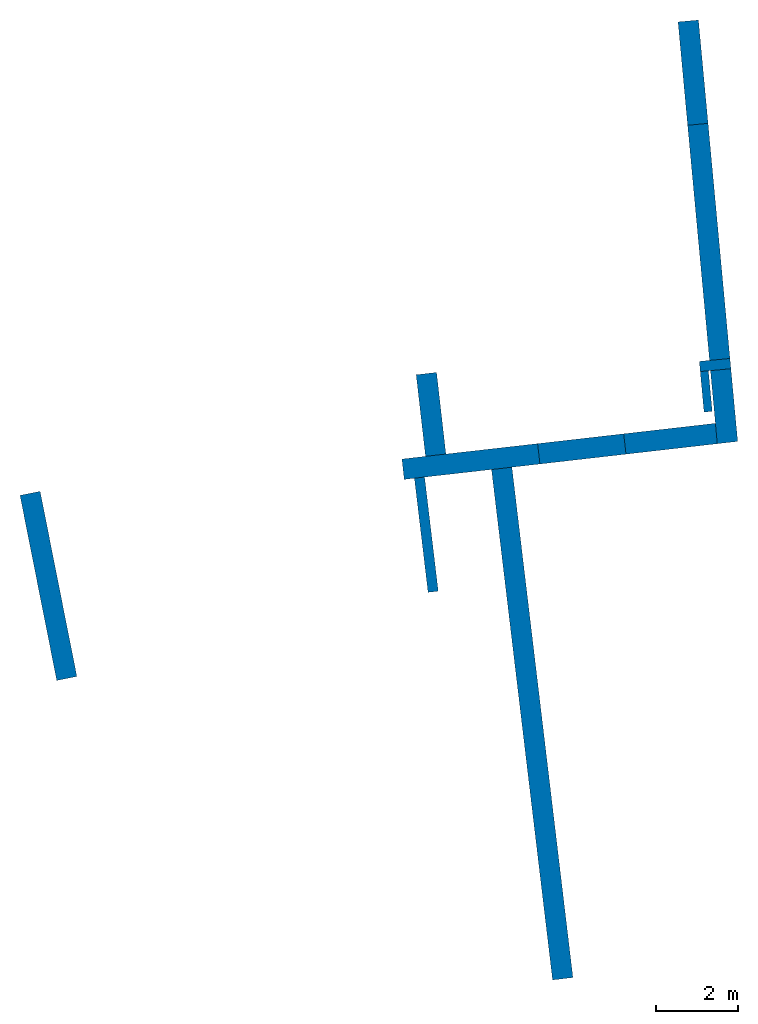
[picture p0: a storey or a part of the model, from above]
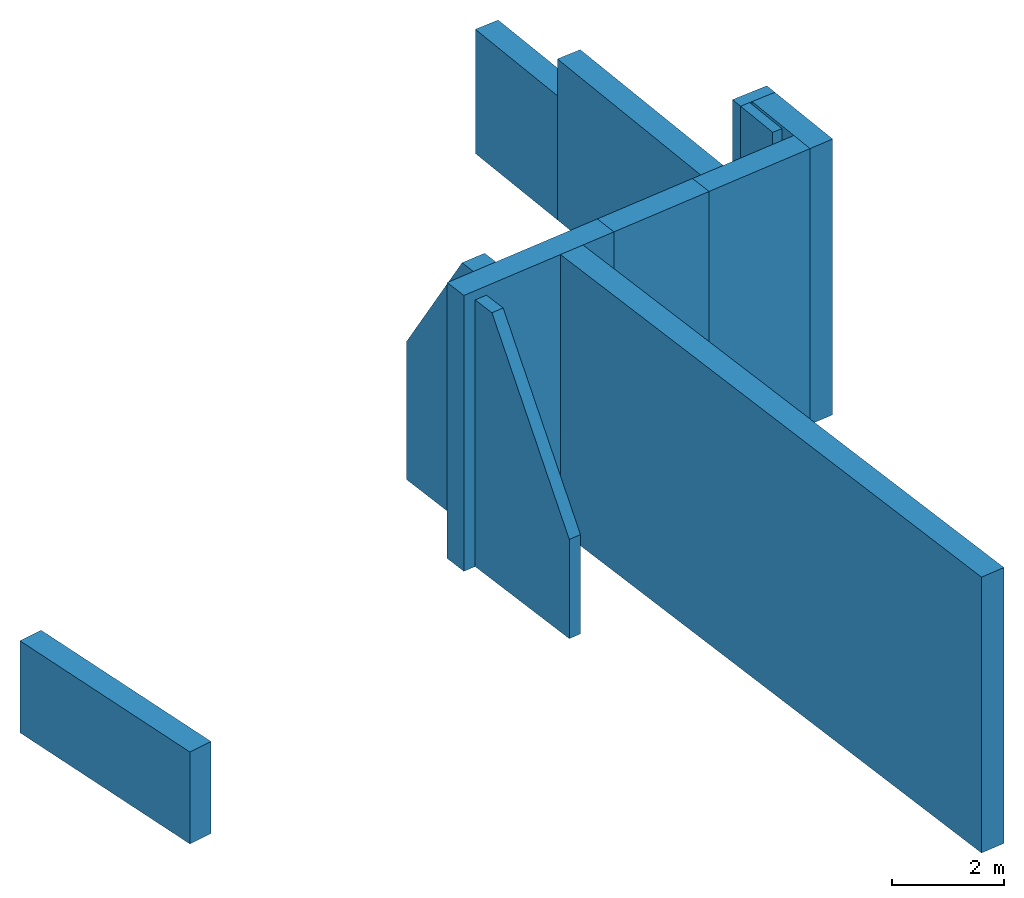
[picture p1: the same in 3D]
Properties of the parts of a building model (IFC2X3)

# File
Description: ViewDefinition [CoordinationView_V2.0], RevitIdentifiers [ContentGUID: 4f80ab2a-d969-4c19-8510-030c973d2cf4, VersionGUID: aa1a487a-609a-4066-8ef7-fdd702d4bbbf, NumberOfSaves: 51], CoordinateReference [CoordinateBase: Coordonnées partagées, ProjectSite: Site par défaut]
File name: Monte_Christo_APD2.ifc
Time: 2026-05-22T14:50:11+01:00
Written by: ODA SDAI 25.12
Made in: Autodesk - Revit 26.4.10.51 (FRA) - 26.4.10.51

# IfcProject, MOE250885-1
LongName: Requalification, désamaintage, gestoin de plomb, deconstruction

# IfcSite, Default
RefLatitude: 42, 24, 53, 508911; RefLongitude: -71, -15, -29, -58837; RefElevation: 0 cm

# IfcBuilding
Pset_BuildingCommon - NumberOfStoreys: 5

# IfcBuildingStorey (5)
Name | LongName | Elevation (cm)
R-1 | R-1 | -300
Fondations | Fondations | -100
RdC | RdC | 0
R+1 | R+1 | 300
R+2 | R+2 | 600

# IfcBuildingElementProxy: LBTS-26-m_sout.L.370H-ESS-OLL:370*215 (theorique) (2)
In: RdC
Type - Material: 00-Béton
Pset_BuildingElementProxyCommon - Reference: 370*215 (theorique); sets with these values: 2
Name (LBTS-26-m_sout.L.370H-ESS-OLL:370*215 (theorique):...)
201774
201784

# IfcBuildingElementProxy: LBTS-26-m_sout.L.370H-ESS-OLL:370*215 (theorique) coupé à 160, LBTS-26-m_sout.L.370H-ESS-OLL:370*215 (theorique) coupé à 160:201796
In: RdC
Type - Material: 00-Béton
Pset_BuildingElementProxyCommon - Reference: 370*215 (theorique) coupé à 160; sets with these values: 2

# IfcBuildingElementProxy: LBTS-26-m_sout.L9_250H-ESS-OLL:L9 250H x 130B (8)
In: RdC
Type - Material: 00-Béton
Pset_BuildingElementProxyCommon - Reference: L9 250H x 130B; sets with these values: 2
Name (LBTS-26-m_sout.L9_250H-ESS-OLL:L9 250H x 130B:...)
192146
192699
192711
192719
202022
202201
202209
202223

# IfcColumn: LBTS-25-poteau_rectangulaire-ESS-OLL:Pt.001, LBTS-25-poteau_rectangulaire-ESS-OLL:Pt.001:182199
In: R-1
Type - PredefinedType: COLUMN; Material: 00-Béton
Type - Pset_ColumnCommon - LoadBearing: yes
Pset_ColumnCommon - IsExternal: no; Reference: Pt.001
Pset_QuantityTakeOff - Reference: Pt.001; sets with these values: 2

# IfcOpeningElement: Opening, Mur de base:Existant 50:238493:1
In: R-1
Pset_OpeningElementCommon - Reference: Existant 50; sets with these values: 2

# IfcSlab: LBTS-25-SF+GB-ESS2-OLL:SF.001, LBTS-25-SF+GB-ESS2-OLL:SF.001:220215
In: RdC
Type - PredefinedType: BASESLAB; Material: 00-GB
Pset_QuantityTakeOff - Reference: SF.001; sets with these values: 2
Pset_SlabCommon - IsExternal: no; Reference: SF.001

# IfcSlab: Sol:Sol existant (2)
In: RdC
Type - PredefinedType: FLOOR; Material: 04-Existant 40 cm
Pset_QuantityTakeOff - Reference: Sol existant; sets with these values: 2
Pset_SlabCommon - IsExternal: no; LoadBearing: yes; PitchAngle: 0 deg; Reference: Sol existant
Name (Sol:Sol existant:...)
197333
216291

# IfcSlab: Sol:Sol modifié hors lot, Sol:Sol modifié hors lot:247380
In: RdC
Type - PredefinedType: FLOOR; Material: 04-hors lot 40 cm
Pset_QuantityTakeOff - Reference: Sol modifié hors lot; sets with these values: 2
Pset_SlabCommon - IsExternal: no; LoadBearing: yes; PitchAngle: 0 deg; Reference: Sol modifié hors lot

# IfcSlab: Sol:Terre végétale, Sol:Terre végétale:244847
In: RdC
Type - PredefinedType: FLOOR
Type - Pset_SlabCommon - ThermalTransmittance: 0.558 kg/K/s3
Material: 05-Terre ajoutée, 05-Couche de forme 2
Pset_QuantityTakeOff - Reference: Terre végétale; sets with these values: 2
Pset_SlabCommon - IsExternal: no; LoadBearing: yes; PitchAngle: 0 deg; Reference: Terre végétale

# IfcSlab: Sol:Terre végétale 2, Sol:Terre végétale 2:182091
In: RdC
Type - PredefinedType: FLOOR; Material: 05-Terre ajoutée 50 cm, 05-Terre 30 cm
Type - Pset_SlabCommon - ThermalTransmittance: 1.04625 kg/K/s3
Pset_QuantityTakeOff - Reference: Terre végétale 2; sets with these values: 2
Pset_SlabCommon - IsExternal: no; LoadBearing: yes; PitchAngle: 0 deg; Reference: Terre végétale 2

# IfcSlab: Sol:Terre végétale arbres (6)
In: RdC
Type - PredefinedType: FLOOR; Material: 05-Terre arbres 150 cm
Type - Pset_SlabCommon - ThermalTransmittance: 0.558 kg/K/s3
Pset_QuantityTakeOff - Reference: Terre végétale arbres; sets with these values: 2
Pset_SlabCommon - IsExternal: no; LoadBearing: yes; PitchAngle: 0 deg; Reference: Terre végétale arbres
Name (Sol:Terre végétale arbres:...)
246483
246483:2
246483:3
246483:4
246483:5
246483:6

# IfcSlab: Sol:plateforme finie, Sol:plateforme finie:181933
In: RdC
Type - PredefinedType: FLOOR; Material: 05-Couche de forme 1 30 cm, 05-Couche de forme 2 120 cm
Type - Pset_SlabCommon - ThermalTransmittance: 0.558 kg/K/s3
Pset_QuantityTakeOff - Reference: plateforme finie; sets with these values: 2
Pset_SlabCommon - Reference: plateforme finie; IsExternal: no; LoadBearing: yes; PitchAngle: 0 deg

# IfcWall: Mur de base:Voile B.A. 50, Mur de base:Voile B.A. 50:198697
In: R-1
Type - PredefinedType: STANDARD; Material: 00-Béton 50 cm
Pset_QuantityTakeOff - Reference: Voile B.A. 50; sets with these values: 2
Pset_WallCommon - LoadBearing: yes; IsExternal: yes; ExtendToStructure: no; Reference: Voile B.A. 50

# IfcWallStandardCase: Mur de base:Existant 20 (2)
In: RdC
Type - PredefinedType: STANDARD; Material: 04-Existant 20 cm
Pset_QuantityTakeOff - Reference: Existant 20; sets with these values: 2
Pset_WallCommon - LoadBearing: yes; IsExternal: yes; Reference: Existant 20
Name (Mur de base:Existant 20:...) | ExtendToStructure
219162 | yes
219373 | no

# IfcWallStandardCase: Mur de base:Existant 25 (6)
Type - PredefinedType: STANDARD; Material: 04-Existant 25 cm
Pset_QuantityTakeOff - Reference: Existant 25; sets with these values: 2
Pset_WallCommon - LoadBearing: yes; IsExternal: yes; Reference: Existant 25
Name (Mur de base:Existant 25:...) | In | ExtendToStructure
197031 | R-1 | no
197139 | RdC | yes
198242 | RdC | yes
198895 | RdC | yes
204241 | RdC | yes
204914 | RdC | yes

# IfcWallStandardCase: Mur de base:Existant 50 (8)
In: R-1
Type - PredefinedType: STANDARD; Material: 04-Existant 50 cm
Pset_QuantityTakeOff - Reference: Existant 50; sets with these values: 2
Pset_WallCommon - LoadBearing: yes; IsExternal: yes; Reference: Existant 50
Name (Mur de base:Existant 50:...) | ExtendToStructure
197007 | yes
197013 | no
197019 | no
197025 | no
199165 | no
201073 | no
204518 | yes
238493 | no

# IfcWallStandardCase: Mur de base:Voile B.A. 20, Mur de base:Voile B.A. 20:196683
In: R-1
Type - PredefinedType: STANDARD; Material: 00-Béton 20 cm
Pset_QuantityTakeOff - Reference: Voile B.A. 20; sets with these values: 2
Pset_WallCommon - LoadBearing: yes; Reference: Voile B.A. 20; IsExternal: yes; ExtendToStructure: no
